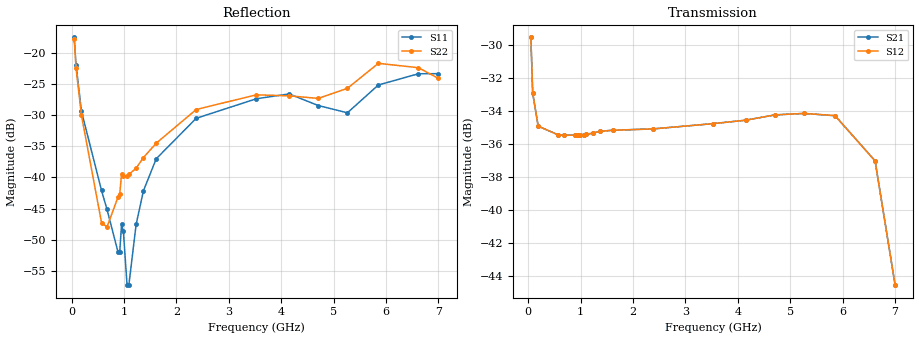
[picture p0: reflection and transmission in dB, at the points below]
! Integrated Device Technology
! Corporate Headquarters
! 6024 Silver Creek Valley Road
! San Jose, CA 95138  USA
! Phone:  1-408-284-8200
! Toll Free:  1-800-223-1366
! Webpage:  http://www.idt.com/
! Timing and RF Division
! 515 Groton Road, Suite 102
! Westford, MA 01886-6024
! Device:  F2258
! Description: Voltage Variable RF Attenuator
! Frequency:  50.0 -  6000.00 MHz
! Package:  3x3 mm Thin QFN Plastic Package: 16 pin
! Ports:  2 RF, 2 DC
!  Pin  1  = NC
!  Pin  2  = NC
!  Pin  3  = RF2  = Port 2
!  Pin  4  = GND
!  Pin  5  = Vdd
!  Pin  6  = NC
!  Pin  7  = VCTRL
!  Pin  8  = NC
!  Pin  9  = GND
!  Pin 10  = RF1  = Port 1
!  Pin 11  = NC
!  Pin 12  = NC
!  Pin 13  = NC
!  Pin 14  = NC
!  Pin 15  = NC
!  Pin 16  = NC
! Vcntrl:  2.320 Volts
! Vdd:  +3.300 Volts
! Current:  1.147 mA
! Data:  The device was measured on a the F2258 evaluation board which has
!  individual transmission lines to the RF pins.  Data was collected
!  using a calibrated network analyzer.  The evaluation board was
!  de-embedded using a TRL calibration technique.
!  The reference plane is the edge of the package pin.
! Misc:  SN 10
!  Action Tracker AT0285
! Date Measured:  2014-12-10
! Date:  2016-01-13  MJV
! Note:
!  Integrated Device Technology supplies this data as a sample of measured
!  data at the package pin for this product.  Your particular data for this
!  product may vary.
!  Data was taken at 25 degrees C.
!  Integrated Device Technology reserves the right to change this data at anytime.
!Freq_(GHz)  S11M_(dB)  S11P_(deg)  S21M_(dB)  S21P_(deg)  S12M_(dB)  S12P_(deg)  S22M_(dB)  S22P_(deg)
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# GHz S dB R 50
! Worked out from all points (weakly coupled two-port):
!   201 points, 50 MHz to 7 GHz, reference 50 ohm
!   highest |S21| = -29.53 dB at 50 MHz (marker M1); lowest = -44.5 dB at 7 GHz (marker M2)
!   lowest |S11| = -57.3 dB at 1.093 GHz (marker M3), VSWR 1.00, Z = 49.9 + j0.116 ohm
!   |S11| at or under -10 dB: start of sweep to end of sweep
!   |S22| runs from -48.0 to -17.8 dB; largest |S21 - S12| = 7.1e-05
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0.05  -17.56 -111.0  -29.53 -68.6  -29.53 -68.6  -17.81 -111.5
0.08475  -21.98 -107.5  -32.90 -48.8  -32.90 -48.8  -22.47 -107.9
0.189  -29.42 -109.5  -34.91 -24.8  -34.91 -24.8  -30.08 -110.9
0.57125  -42.10 -124.9  -35.44 -10.4  -35.44 -10.4  -47.25 -167.6
0.6755  -45.12 -132.3  -35.46 -9.4  -35.46 -9.4  -47.96 149.9
0.884  -51.91 166.2  -35.46 -8.4  -35.46 -8.4  -43.21 121.8
0.91875  -51.95 150.5  -35.45 -8.3  -35.45 -8.3  -42.71 119.6
0.9535  -47.54 -162.8  -35.46 -8.2  -35.46 -8.2  -39.43 124.6
0.98825  -48.61 -174.3  -35.44 -8.0  -35.44 -8.1  -39.75 122.5
1.05775  -57.19 154.6  -35.42 -7.9  -35.43 -7.9  -39.73 108.2
1.0925  -57.27 122.0  -35.41 -7.9  -35.41 -7.9  -39.53 104.4
1.2315  -47.55 46.3  -35.34 -7.9  -35.33 -7.9  -38.53 82.8
1.3705  -42.17 37.4  -35.22 -8.3  -35.23 -8.3  -36.83 69.5
1.61375  -37.03 32.8  -35.16 -9.6  -35.16 -9.6  -34.53 55.4
2.37825  -30.53 48.1  -35.08 -13.1  -35.08 -13.1  -29.12 44.5
3.525  -27.40 91.7  -34.76 -19.5  -34.76 -19.5  -26.77 68.2
4.1505  -26.62 104.9  -34.55 -24.0  -34.55 -23.9  -26.93 75.7
4.7065  -28.48 95.7  -34.23 -28.6  -34.23 -28.7  -27.34 59.4
5.2625  -29.65 54.3  -34.14 -34.8  -34.14 -34.7  -25.73 22.1
5.85325  -25.19 29.9  -34.28 -45.5  -34.27 -45.4  -21.72 -2.0
6.61775  -23.39 49.7  -37.01 -68.7  -37.03 -68.6  -22.42 -43.9
7  -23.38 84.5  -44.54 -61.5  -44.55 -61.2  -24.13 -130.1
